VERSION 5.7 ;
  NOWIREEXTENSIONATPIN ON ;
  DIVIDERCHAR "/" ;
  BUSBITCHARS "[]" ;
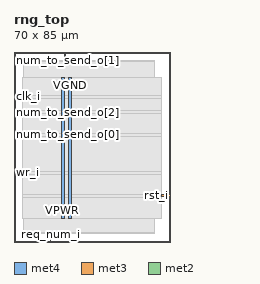
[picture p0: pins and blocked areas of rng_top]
MACRO rng_top
  CLASS BLOCK ;
  FOREIGN rng_top ;
  ORIGIN 0.000 0.000 ;
  SIZE 70.000 BY 85.000 ;
  PIN VGND
    DIRECTION INOUT ;
    USE GROUND ;
    PORT
      LAYER met4 ;
        RECT 24.340 10.640 25.940 73.680 ;
    END
  END VGND
  PIN VPWR
    DIRECTION INOUT ;
    USE POWER ;
    PORT
      LAYER met4 ;
        RECT 21.040 10.640 22.640 73.680 ;
    END
  END VPWR
  PIN clk_i
    DIRECTION INPUT ;
    USE SIGNAL ;
    ANTENNAGATEAREA 0.852000 ;
    PORT
      LAYER met3 ;
        RECT 0.000 64.640 4.000 65.240 ;
    END
  END clk_i
  PIN num_to_send_o[0]
    DIRECTION OUTPUT ;
    USE SIGNAL ;
    ANTENNADIFFAREA 0.445500 ;
    PORT
      LAYER met3 ;
        RECT 0.000 47.640 4.000 48.240 ;
    END
  END num_to_send_o[0]
  PIN num_to_send_o[1]
    DIRECTION OUTPUT ;
    USE SIGNAL ;
    ANTENNADIFFAREA 0.445500 ;
    PORT
      LAYER met2 ;
        RECT 22.630 81.000 22.910 85.000 ;
    END
  END num_to_send_o[1]
  PIN num_to_send_o[2]
    DIRECTION OUTPUT ;
    USE SIGNAL ;
    ANTENNADIFFAREA 0.445500 ;
    PORT
      LAYER met3 ;
        RECT 0.000 57.840 4.000 58.440 ;
    END
  END num_to_send_o[2]
  PIN req_num_i
    DIRECTION INPUT ;
    USE SIGNAL ;
    ANTENNAGATEAREA 0.196500 ;
    PORT
      LAYER met2 ;
        RECT 16.190 0.000 16.470 4.000 ;
    END
  END req_num_i
  PIN rst_i
    DIRECTION INPUT ;
    USE SIGNAL ;
    ANTENNAGATEAREA 0.196500 ;
    PORT
      LAYER met3 ;
        RECT 66.000 20.440 70.000 21.040 ;
    END
  END rst_i
  PIN wr_i
    DIRECTION INPUT ;
    USE SIGNAL ;
    ANTENNAGATEAREA 0.196500 ;
    PORT
      LAYER met3 ;
        RECT 0.000 30.640 4.000 31.240 ;
    END
  END wr_i
  OBS
      LAYER nwell ;
        RECT 5.330 10.795 64.590 73.630 ;
      LAYER li1 ;
        RECT 5.520 10.795 64.400 73.525 ;
      LAYER met1 ;
        RECT 4.210 10.640 64.400 73.680 ;
      LAYER met2 ;
        RECT 4.230 80.720 22.350 81.000 ;
        RECT 23.190 80.720 62.930 81.000 ;
        RECT 4.230 4.280 62.930 80.720 ;
        RECT 4.230 4.000 15.910 4.280 ;
        RECT 16.750 4.000 62.930 4.280 ;
      LAYER met3 ;
        RECT 3.990 65.640 66.000 73.605 ;
        RECT 4.400 64.240 66.000 65.640 ;
        RECT 3.990 58.840 66.000 64.240 ;
        RECT 4.400 57.440 66.000 58.840 ;
        RECT 3.990 48.640 66.000 57.440 ;
        RECT 4.400 47.240 66.000 48.640 ;
        RECT 3.990 31.640 66.000 47.240 ;
        RECT 4.400 30.240 66.000 31.640 ;
        RECT 3.990 21.440 66.000 30.240 ;
        RECT 3.990 20.040 65.600 21.440 ;
        RECT 3.990 10.715 66.000 20.040 ;
  END
END rng_top
END LIBRARY

